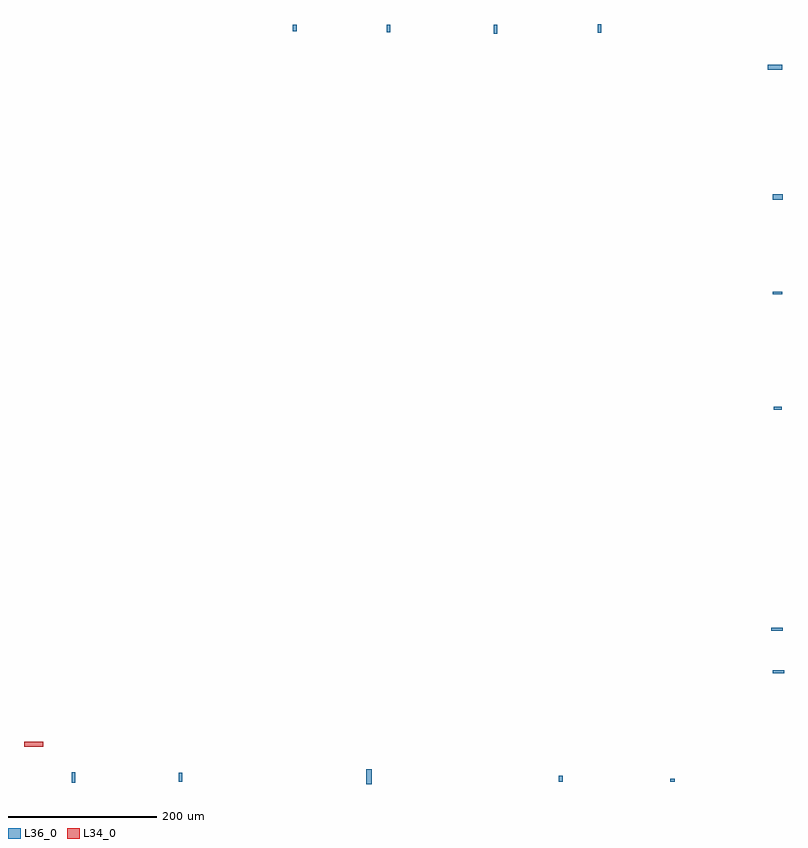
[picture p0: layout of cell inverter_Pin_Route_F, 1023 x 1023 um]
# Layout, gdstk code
import gdstk
lib = gdstk.Library(unit=1e-6, precision=1e-09)
def R(c, l, rs):  # rectangles x0, y0, x1, y1
    for r in rs: c.add(gdstk.rectangle(r[:2], r[2:], *l))
L34_0 = (34, 0)
L36_0 = (36, 0)

inverter_pin_route_f = lib.new_cell('inverter_Pin_Route_F')
R(inverter_pin_route_f, L34_0, [(439,488,465,495)])
R(inverter_pin_route_f, L36_0, [(900,438,907,458), (503,440,508,454), (647,441,652,453), (1159,441,1164,449), (1309,441,1315,445), (1447,587,1462,591), (1445,644,1460,648), (1448,942,1459,946), (1446.6,1097.4,1459.5,1100.4), (1446.6,1224.3,1460.1,1231.5), (1440,1399.5,1459.5,1406.4), (1071,1448,1076,1460), (1211,1449,1216,1461), (927,1450,932,1460), (801,1451,806,1460)])

lib.write_gds('inverter_Pin_Route_F.gds')
